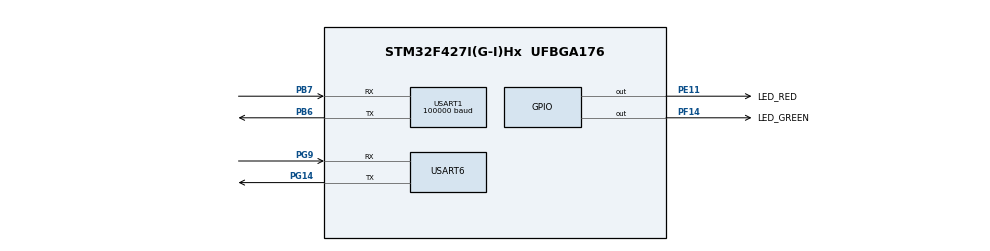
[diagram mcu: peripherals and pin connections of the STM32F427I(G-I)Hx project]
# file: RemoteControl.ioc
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Dma.Request0=USART1_RX
Dma.USART1_RX.0.Direction=DMA_PERIPH_TO_MEMORY
Dma.USART1_RX.0.FIFOMode=DMA_FIFOMODE_DISABLE
Dma.USART1_RX.0.Instance=DMA2_Stream2
Dma.USART1_RX.0.MemDataAlignment=DMA_MDATAALIGN_BYTE
Dma.USART1_RX.0.MemInc=DMA_MINC_ENABLE
Dma.USART1_RX.0.Mode=DMA_CIRCULAR
Dma.USART1_RX.0.PeriphDataAlignment=DMA_PDATAALIGN_BYTE
Dma.USART1_RX.0.PeriphInc=DMA_PINC_DISABLE
Dma.USART1_RX.0.Priority=DMA_PRIORITY_LOW
Mcu.Family=STM32F4
Mcu.Name=STM32F427I(G-I)Hx
Mcu.Package=UFBGA176
NVIC.DMA2_Stream2_IRQn=true\:0\:0\:false\:false\:true\:false\:true
NVIC.PriorityGroup=NVIC_PRIORITYGROUP_4
NVIC.USART1_IRQn=true\:0\:0\:false\:false\:true\:true\:true
NVIC.USART6_IRQn=true\:0\:0\:false\:false\:true\:true\:true
PA13.Mode=Serial_Wire
PA13.Signal=SYS_JTMS-SWDIO
PA14.Mode=Serial_Wire
PA14.Signal=SYS_JTCK-SWCLK
PB6.Mode=Asynchronous
PB6.Signal=USART1_TX
PB7.Mode=Asynchronous
PB7.Signal=USART1_RX
PE11.GPIO_Label=LED_RED
PE11.Signal=GPIO_Output
PF14.GPIO_Label=LED_GREEN
PF14.Signal=GPIO_Output
PG14.Mode=Asynchronous
PG14.Signal=USART6_TX
PG9.Mode=Asynchronous
PG9.Signal=USART6_RX
PH0/OSC_IN.Mode=HSE-External-Oscillator
PH0/OSC_IN.Signal=RCC_OSC_IN
PH1/OSC_OUT.Mode=HSE-External-Oscillator
PH1/OSC_OUT.Signal=RCC_OSC_OUT
ProjectManager.HeapSize=0x200
ProjectManager.StackSize=0x400
ProjectManager.TargetToolchain=MDK-ARM V5
RCC.48MHZClocksFreq_Value=84000000
RCC.AHBFreq_Value=168000000
RCC.APB1CLKDivider=RCC_HCLK_DIV4
RCC.APB1Freq_Value=42000000
RCC.APB1TimFreq_Value=84000000
RCC.APB2CLKDivider=RCC_HCLK_DIV2
RCC.APB2Freq_Value=84000000
RCC.APB2TimFreq_Value=168000000
RCC.CortexFreq_Value=168000000
RCC.HCLKFreq_Value=168000000
RCC.HSE_VALUE=12000000
RCC.HSI_VALUE=16000000
RCC.LSE_VALUE=32768
RCC.PLLM=6
RCC.PLLN=168
RCC.PLLSourceVirtual=RCC_PLLSOURCE_HSE
RCC.SYSCLKFreq_VALUE=168000000
RCC.SYSCLKSource=RCC_SYSCLKSOURCE_PLLCLK
RCC.VCOOutputFreq_Value=336000000
USART1.BaudRate=100000
USART1.Parity=PARITY_EVEN
USART1.VirtualMode=VM_ASYNC
USART6.VirtualMode=VM_ASYNC
board=RemoteControl

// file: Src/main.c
/**
  ******************************************************************************
  * @file           : main.c
  * @brief          : Main program body
  ******************************************************************************
  ** This notice applies to any and all portions of this file
  * that are not between comment pairs USER CODE BEGIN and
  * USER CODE END. Other portions of this file, whether
  * inserted by the user or by software development tools
  * are owned by their respective copyright owners.
  *
  * COPYRIGHT(c) 2018 STMicroelectronics
  *
  * Redistribution and use in source and binary forms, with or without modification,
  * are permitted provided that the following conditions are met:
  *   1. Redistributions of source code must retain the above copyright notice,
  *      this list of conditions and the following disclaimer.
  *   2. Redistributions in binary form must reproduce the above copyright notice,
  *      this list of conditions and the following disclaimer in the documentation
  *      and/or other materials provided with the distribution.
  *   3. Neither the name of STMicroelectronics nor the names of its contributors
  *      may be used to endorse or promote products derived from this software
  *      without specific prior written permission.
  *
  * THIS SOFTWARE IS PROVIDED BY THE COPYRIGHT HOLDERS AND CONTRIBUTORS "AS IS"
  * AND ANY EXPRESS OR IMPLIED WARRANTIES, INCLUDING, BUT NOT LIMITED TO, THE
  * IMPLIED WARRANTIES OF MERCHANTABILITY AND FITNESS FOR A PARTICULAR PURPOSE ARE
  * DISCLAIMED. IN NO EVENT SHALL THE COPYRIGHT HOLDER OR CONTRIBUTORS BE LIABLE
  * FOR ANY DIRECT, INDIRECT, INCIDENTAL, SPECIAL, EXEMPLARY, OR CONSEQUENTIAL
  * DAMAGES (INCLUDING, BUT NOT LIMITED TO, PROCUREMENT OF SUBSTITUTE GOODS OR
  * SERVICES; LOSS OF USE, DATA, OR PROFITS; OR BUSINESS INTERRUPTION) HOWEVER
  * CAUSED AND ON ANY THEORY OF LIABILITY, WHETHER IN CONTRACT, STRICT LIABILITY,
  * OR TORT (INCLUDING NEGLIGENCE OR OTHERWISE) ARISING IN ANY WAY OUT OF THE USE
  * OF THIS SOFTWARE, EVEN IF ADVISED OF THE POSSIBILITY OF SUCH DAMAGE.
  *
  ******************************************************************************
  */
#include "main.h"
#include "stm32f4xx_hal.h"
#include "dma.h"
#include "usart.h"
#include "gpio.h"

/* USER CODE BEGIN Includes */
#include "bsp_uart.h"
/* USER CODE END Includes */

/* USER CODE BEGIN PV */
/* Private variables ---------------------------------------------------------*/
extern rc_info_t rc;
char buf[200];
int count;
/* USER CODE END PV */

void SystemClock_Config(void);

/* USER CODE BEGIN PFP */
/* Private function prototypes -----------------------------------------------*/

/* USER CODE END PFP */

int main(void)
{

  /* MCU Configuration----------------------------------------------------------*/

  /* Reset of all peripherals, Initializes the Flash interface and the Systick. */
  HAL_Init();

  /* Configure the system clock */
  SystemClock_Config();

  /* Initialize all configured peripherals */
  MX_GPIO_Init();
  MX_DMA_Init();
  MX_USART6_UART_Init();
  MX_USART1_UART_Init();
  /* USER CODE BEGIN 2 */
	led_off();
	/* open dbus uart receive it */
	dbus_uart_init();
  /* USER CODE END 2 */

  /* Infinite loop */
  while (1)
  {

  /* USER CODE BEGIN 3 */

	sprintf(buf, "CH1: %4d  CH2: %4d  CH3: %4d  CH4: %4d  SW1: %1d  SW2: %1d \n", rc.ch1, rc.ch2, rc.ch3, rc.ch4, rc.sw1, rc.sw2);
	//HAL_UART_Transmit(&huart6, (uint8_t *)buf, (COUNTOF(buf) - 1), 55);
//	HAL_Delay(50);
//
//	if (count==10)
//	{
//		HAL_GPIO_TogglePin(LED_GREEN_GPIO_Port, LED_GREEN_Pin);
//		count=0;
//	}
  }
  /* USER CODE END 3 */

}

void SystemClock_Config(void)
{

  RCC_OscInitTypeDef RCC_OscInitStruct;
  RCC_ClkInitTypeDef RCC_ClkInitStruct;

    /**Configure the main internal regulator output voltage
    */
  __HAL_RCC_PWR_CLK_ENABLE();

  __HAL_PWR_VOLTAGESCALING_CONFIG(PWR_REGULATOR_VOLTAGE_SCALE1);

    /**Initializes the CPU, AHB and APB busses clocks
    */
  RCC_OscInitStruct.OscillatorType = RCC_OSCILLATORTYPE_HSE;
  RCC_OscInitStruct.HSEState = RCC_HSE_ON;
  RCC_OscInitStruct.PLL.PLLState = RCC_PLL_ON;
  RCC_OscInitStruct.PLL.PLLSource = RCC_PLLSOURCE_HSE;
  RCC_OscInitStruct.PLL.PLLM = 6;
  RCC_OscInitStruct.PLL.PLLN = 180;
  RCC_OscInitStruct.PLL.PLLP = RCC_PLLP_DIV2;
  RCC_OscInitStruct.PLL.PLLQ = 4;
  if (HAL_RCC_OscConfig(&RCC_OscInitStruct) != HAL_OK)
  {
    _Error_Handler(__FILE__, __LINE__);
  }

    /**Initializes the CPU, AHB and APB busses clocks
    */
  RCC_ClkInitStruct.ClockType = RCC_CLOCKTYPE_HCLK|RCC_CLOCKTYPE_SYSCLK
                              |RCC_CLOCKTYPE_PCLK1|RCC_CLOCKTYPE_PCLK2;
  RCC_ClkInitStruct.SYSCLKSource = RCC_SYSCLKSOURCE_PLLCLK;
  RCC_ClkInitStruct.AHBCLKDivider = RCC_SYSCLK_DIV1;
  RCC_ClkInitStruct.APB1CLKDivider = RCC_HCLK_DIV4;
  RCC_ClkInitStruct.APB2CLKDivider = RCC_HCLK_DIV2;

  if (HAL_RCC_ClockConfig(&RCC_ClkInitStruct, FLASH_LATENCY_5) != HAL_OK)
  {
    _Error_Handler(__FILE__, __LINE__);
  }

    /**Configure the Systick interrupt time
    */
  HAL_SYSTICK_Config(HAL_RCC_GetHCLKFreq()/1000);

    /**Configure the Systick
    */
  HAL_SYSTICK_CLKSourceConfig(SYSTICK_CLKSOURCE_HCLK);

  /* SysTick_IRQn interrupt configuration */
  HAL_NVIC_SetPriority(SysTick_IRQn, 0, 0);
}

void _Error_Handler(char *file, int line)
{
  while(1)
  {
  }
}

/************************ (C) COPYRIGHT STMicroelectronics *****END OF FILE****/
